VERSION 5.7 ;
  NOWIREEXTENSIONATPIN ON ;
  DIVIDERCHAR "/" ;
  BUSBITCHARS "[]" ;
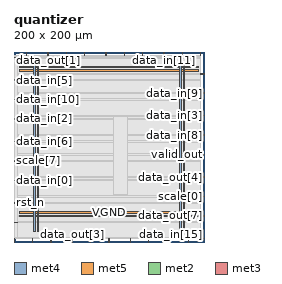
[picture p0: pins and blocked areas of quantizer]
MACRO quantizer
  CLASS BLOCK ;
  FOREIGN quantizer ;
  ORIGIN 0.000 0.000 ;
  SIZE 200.000 BY 200.000 ;
  PIN VGND
    DIRECTION INOUT ;
    USE GROUND ;
    PORT
      LAYER met4 ;
        RECT 24.340 10.640 25.940 187.920 ;
    END
    PORT
      LAYER met4 ;
        RECT 177.940 10.640 179.540 187.920 ;
    END
    PORT
      LAYER met5 ;
        RECT 5.280 30.030 194.360 31.630 ;
    END
    PORT
      LAYER met5 ;
        RECT 5.280 183.210 194.360 184.810 ;
    END
  END VGND
  PIN VPWR
    DIRECTION INOUT ;
    USE POWER ;
    PORT
      LAYER met4 ;
        RECT 21.040 10.640 22.640 187.920 ;
    END
    PORT
      LAYER met4 ;
        RECT 174.640 10.640 176.240 187.920 ;
    END
    PORT
      LAYER met5 ;
        RECT 5.280 26.730 194.360 28.330 ;
    END
    PORT
      LAYER met5 ;
        RECT 5.280 179.910 194.360 181.510 ;
    END
  END VPWR
  PIN clk
    DIRECTION INPUT ;
    USE SIGNAL ;
    ANTENNAGATEAREA 0.852000 ;
    PORT
      LAYER met2 ;
        RECT 99.910 0.000 100.190 4.000 ;
    END
  END clk
  PIN data_in[0]
    DIRECTION INPUT ;
    USE SIGNAL ;
    ANTENNAGATEAREA 0.159000 ;
    PORT
      LAYER met3 ;
        RECT 0.000 64.640 4.000 65.240 ;
    END
  END data_in[0]
  PIN data_in[10]
    DIRECTION INPUT ;
    USE SIGNAL ;
    ANTENNAGATEAREA 0.159000 ;
    PORT
      LAYER met3 ;
        RECT 0.000 149.640 4.000 150.240 ;
    END
  END data_in[10]
  PIN data_in[11]
    DIRECTION INPUT ;
    USE SIGNAL ;
    ANTENNAGATEAREA 0.159000 ;
    PORT
      LAYER met2 ;
        RECT 157.870 196.000 158.150 200.000 ;
    END
  END data_in[11]
  PIN data_in[12]
    DIRECTION INPUT ;
    USE SIGNAL ;
    ANTENNAGATEAREA 0.159000 ;
    PORT
      LAYER met2 ;
        RECT 116.010 196.000 116.290 200.000 ;
    END
  END data_in[12]
  PIN data_in[13]
    DIRECTION INPUT ;
    USE SIGNAL ;
    ANTENNAGATEAREA 0.159000 ;
    PORT
      LAYER met2 ;
        RECT 135.330 196.000 135.610 200.000 ;
    END
  END data_in[13]
  PIN data_in[14]
    DIRECTION INPUT ;
    USE SIGNAL ;
    ANTENNAGATEAREA 0.213000 ;
    PORT
      LAYER met2 ;
        RECT 35.510 196.000 35.790 200.000 ;
    END
  END data_in[14]
  PIN data_in[15]
    DIRECTION INPUT ;
    USE SIGNAL ;
    ANTENNAGATEAREA 0.126000 ;
    PORT
      LAYER met2 ;
        RECT 183.630 0.000 183.910 4.000 ;
    END
  END data_in[15]
  PIN data_in[1]
    DIRECTION INPUT ;
    USE SIGNAL ;
    ANTENNAGATEAREA 0.213000 ;
    PORT
      LAYER met2 ;
        RECT 161.090 0.000 161.370 4.000 ;
    END
  END data_in[1]
  PIN data_in[2]
    DIRECTION INPUT ;
    USE SIGNAL ;
    ANTENNAGATEAREA 0.159000 ;
    PORT
      LAYER met3 ;
        RECT 0.000 129.240 4.000 129.840 ;
    END
  END data_in[2]
  PIN data_in[3]
    DIRECTION INPUT ;
    USE SIGNAL ;
    ANTENNAGATEAREA 0.213000 ;
    PORT
      LAYER met3 ;
        RECT 196.000 132.640 200.000 133.240 ;
    END
  END data_in[3]
  PIN data_in[4]
    DIRECTION INPUT ;
    USE SIGNAL ;
    ANTENNAGATEAREA 0.213000 ;
    PORT
      LAYER met2 ;
        RECT 54.830 196.000 55.110 200.000 ;
    END
  END data_in[4]
  PIN data_in[5]
    DIRECTION INPUT ;
    USE SIGNAL ;
    ANTENNAGATEAREA 0.159000 ;
    PORT
      LAYER met3 ;
        RECT 0.000 170.040 4.000 170.640 ;
    END
  END data_in[5]
  PIN data_in[6]
    DIRECTION INPUT ;
    USE SIGNAL ;
    ANTENNAGATEAREA 0.159000 ;
    PORT
      LAYER met3 ;
        RECT 0.000 105.440 4.000 106.040 ;
    END
  END data_in[6]
  PIN data_in[7]
    DIRECTION INPUT ;
    USE SIGNAL ;
    ANTENNAGATEAREA 0.213000 ;
    PORT
      LAYER met3 ;
        RECT 196.000 3.440 200.000 4.040 ;
    END
  END data_in[7]
  PIN data_in[8]
    DIRECTION INPUT ;
    USE SIGNAL ;
    ANTENNAGATEAREA 0.213000 ;
    PORT
      LAYER met3 ;
        RECT 196.000 112.240 200.000 112.840 ;
    END
  END data_in[8]
  PIN data_in[9]
    DIRECTION INPUT ;
    USE SIGNAL ;
    ANTENNAGATEAREA 0.159000 ;
    PORT
      LAYER met3 ;
        RECT 196.000 156.440 200.000 157.040 ;
    END
  END data_in[9]
  PIN data_out[0]
    DIRECTION OUTPUT TRISTATE ;
    USE SIGNAL ;
    ANTENNADIFFAREA 0.795200 ;
    PORT
      LAYER met2 ;
        RECT 0.090 0.000 0.370 4.000 ;
    END
  END data_out[0]
  PIN data_out[1]
    DIRECTION OUTPUT TRISTATE ;
    USE SIGNAL ;
    ANTENNADIFFAREA 0.795200 ;
    PORT
      LAYER met2 ;
        RECT 12.970 196.000 13.250 200.000 ;
    END
  END data_out[1]
  PIN data_out[2]
    DIRECTION OUTPUT TRISTATE ;
    USE SIGNAL ;
    ANTENNADIFFAREA 0.795200 ;
    PORT
      LAYER met3 ;
        RECT 0.000 20.440 4.000 21.040 ;
    END
  END data_out[2]
  PIN data_out[3]
    DIRECTION OUTPUT TRISTATE ;
    USE SIGNAL ;
    ANTENNADIFFAREA 0.795200 ;
    PORT
      LAYER met2 ;
        RECT 61.270 0.000 61.550 4.000 ;
    END
  END data_out[3]
  PIN data_out[4]
    DIRECTION OUTPUT TRISTATE ;
    USE SIGNAL ;
    ANTENNADIFFAREA 0.795200 ;
    PORT
      LAYER met3 ;
        RECT 196.000 68.040 200.000 68.640 ;
    END
  END data_out[4]
  PIN data_out[5]
    DIRECTION OUTPUT TRISTATE ;
    USE SIGNAL ;
    ANTENNADIFFAREA 0.795200 ;
    PORT
      LAYER met2 ;
        RECT 141.770 0.000 142.050 4.000 ;
    END
  END data_out[5]
  PIN data_out[6]
    DIRECTION OUTPUT TRISTATE ;
    USE SIGNAL ;
    ANTENNADIFFAREA 0.795200 ;
    PORT
      LAYER met2 ;
        RECT 177.190 196.000 177.470 200.000 ;
    END
  END data_out[6]
  PIN data_out[7]
    DIRECTION OUTPUT TRISTATE ;
    USE SIGNAL ;
    ANTENNADIFFAREA 0.795200 ;
    PORT
      LAYER met3 ;
        RECT 196.000 27.240 200.000 27.840 ;
    END
  END data_out[7]
  PIN overflow
    DIRECTION OUTPUT TRISTATE ;
    USE SIGNAL ;
    ANTENNADIFFAREA 0.795200 ;
    PORT
      LAYER met2 ;
        RECT 19.410 0.000 19.690 4.000 ;
    END
  END overflow
  PIN round_mode
    DIRECTION INPUT ;
    USE SIGNAL ;
    ANTENNAGATEAREA 0.196500 ;
    PORT
      LAYER met2 ;
        RECT 38.730 0.000 39.010 4.000 ;
    END
  END round_mode
  PIN rst_n
    DIRECTION INPUT ;
    USE SIGNAL ;
    ANTENNAGATEAREA 0.213000 ;
    PORT
      LAYER met3 ;
        RECT 0.000 40.840 4.000 41.440 ;
    END
  END rst_n
  PIN scale[0]
    DIRECTION INPUT ;
    USE SIGNAL ;
    ANTENNAGATEAREA 0.213000 ;
    PORT
      LAYER met3 ;
        RECT 196.000 47.640 200.000 48.240 ;
    END
  END scale[0]
  PIN scale[1]
    DIRECTION INPUT ;
    USE SIGNAL ;
    ANTENNAGATEAREA 0.126000 ;
    PORT
      LAYER met2 ;
        RECT 80.590 0.000 80.870 4.000 ;
    END
  END scale[1]
  PIN scale[2]
    DIRECTION INPUT ;
    USE SIGNAL ;
    ANTENNAGATEAREA 0.213000 ;
    PORT
      LAYER met3 ;
        RECT 196.000 176.840 200.000 177.440 ;
    END
  END scale[2]
  PIN scale[3]
    DIRECTION INPUT ;
    USE SIGNAL ;
    ANTENNAGATEAREA 0.159000 ;
    PORT
      LAYER met2 ;
        RECT 196.510 196.000 196.790 200.000 ;
    END
  END scale[3]
  PIN scale[4]
    DIRECTION INPUT ;
    USE SIGNAL ;
    ANTENNAGATEAREA 0.213000 ;
    PORT
      LAYER met2 ;
        RECT 74.150 196.000 74.430 200.000 ;
    END
  END scale[4]
  PIN scale[5]
    DIRECTION INPUT ;
    USE SIGNAL ;
    ANTENNAGATEAREA 0.126000 ;
    PORT
      LAYER met2 ;
        RECT 96.690 196.000 96.970 200.000 ;
    END
  END scale[5]
  PIN scale[6]
    DIRECTION INPUT ;
    USE SIGNAL ;
    ANTENNAGATEAREA 0.159000 ;
    PORT
      LAYER met2 ;
        RECT 122.450 0.000 122.730 4.000 ;
    END
  END scale[6]
  PIN scale[7]
    DIRECTION INPUT ;
    USE SIGNAL ;
    ANTENNAGATEAREA 0.159000 ;
    PORT
      LAYER met3 ;
        RECT 0.000 85.040 4.000 85.640 ;
    END
  END scale[7]
  PIN valid_in
    DIRECTION INPUT ;
    USE SIGNAL ;
    ANTENNAGATEAREA 0.247500 ;
    PORT
      LAYER met3 ;
        RECT 0.000 193.840 4.000 194.440 ;
    END
  END valid_in
  PIN valid_out
    DIRECTION OUTPUT TRISTATE ;
    USE SIGNAL ;
    ANTENNADIFFAREA 0.445500 ;
    PORT
      LAYER met3 ;
        RECT 196.000 91.840 200.000 92.440 ;
    END
  END valid_out
  OBS
      LAYER li1 ;
        RECT 5.520 10.795 194.120 187.765 ;
      LAYER met1 ;
        RECT 0.070 10.640 196.810 187.920 ;
      LAYER met2 ;
        RECT 0.100 195.720 12.690 196.000 ;
        RECT 13.530 195.720 35.230 196.000 ;
        RECT 36.070 195.720 54.550 196.000 ;
        RECT 55.390 195.720 73.870 196.000 ;
        RECT 74.710 195.720 96.410 196.000 ;
        RECT 97.250 195.720 115.730 196.000 ;
        RECT 116.570 195.720 135.050 196.000 ;
        RECT 135.890 195.720 157.590 196.000 ;
        RECT 158.430 195.720 176.910 196.000 ;
        RECT 177.750 195.720 196.230 196.000 ;
        RECT 0.100 4.280 196.780 195.720 ;
        RECT 0.650 3.555 19.130 4.280 ;
        RECT 19.970 3.555 38.450 4.280 ;
        RECT 39.290 3.555 60.990 4.280 ;
        RECT 61.830 3.555 80.310 4.280 ;
        RECT 81.150 3.555 99.630 4.280 ;
        RECT 100.470 3.555 122.170 4.280 ;
        RECT 123.010 3.555 141.490 4.280 ;
        RECT 142.330 3.555 160.810 4.280 ;
        RECT 161.650 3.555 183.350 4.280 ;
        RECT 184.190 3.555 196.780 4.280 ;
      LAYER met3 ;
        RECT 4.400 193.440 196.000 194.290 ;
        RECT 3.990 177.840 196.000 193.440 ;
        RECT 3.990 176.440 195.600 177.840 ;
        RECT 3.990 171.040 196.000 176.440 ;
        RECT 4.400 169.640 196.000 171.040 ;
        RECT 3.990 157.440 196.000 169.640 ;
        RECT 3.990 156.040 195.600 157.440 ;
        RECT 3.990 150.640 196.000 156.040 ;
        RECT 4.400 149.240 196.000 150.640 ;
        RECT 3.990 133.640 196.000 149.240 ;
        RECT 3.990 132.240 195.600 133.640 ;
        RECT 3.990 130.240 196.000 132.240 ;
        RECT 4.400 128.840 196.000 130.240 ;
        RECT 3.990 113.240 196.000 128.840 ;
        RECT 3.990 111.840 195.600 113.240 ;
        RECT 3.990 106.440 196.000 111.840 ;
        RECT 4.400 105.040 196.000 106.440 ;
        RECT 3.990 92.840 196.000 105.040 ;
        RECT 3.990 91.440 195.600 92.840 ;
        RECT 3.990 86.040 196.000 91.440 ;
        RECT 4.400 84.640 196.000 86.040 ;
        RECT 3.990 69.040 196.000 84.640 ;
        RECT 3.990 67.640 195.600 69.040 ;
        RECT 3.990 65.640 196.000 67.640 ;
        RECT 4.400 64.240 196.000 65.640 ;
        RECT 3.990 48.640 196.000 64.240 ;
        RECT 3.990 47.240 195.600 48.640 ;
        RECT 3.990 41.840 196.000 47.240 ;
        RECT 4.400 40.440 196.000 41.840 ;
        RECT 3.990 28.240 196.000 40.440 ;
        RECT 3.990 26.840 195.600 28.240 ;
        RECT 3.990 21.440 196.000 26.840 ;
        RECT 4.400 20.040 196.000 21.440 ;
        RECT 3.990 4.440 196.000 20.040 ;
        RECT 3.990 3.575 195.600 4.440 ;
      LAYER met4 ;
        RECT 104.255 49.815 119.305 131.745 ;
  END
END quantizer
END LIBRARY

